VERSION 5.7 ;
  NOWIREEXTENSIONATPIN ON ;
  DIVIDERCHAR "/" ;
  BUSBITCHARS "[]" ;
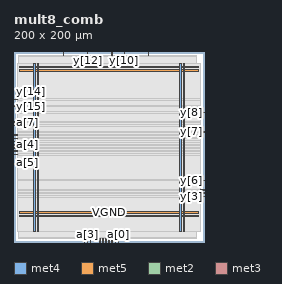
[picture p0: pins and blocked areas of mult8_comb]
MACRO mult8_comb
  CLASS BLOCK ;
  FOREIGN mult8_comb ;
  ORIGIN 0.000 0.000 ;
  SIZE 200.000 BY 200.000 ;
  PIN VGND
    DIRECTION INOUT ;
    USE GROUND ;
    PORT
      LAYER met4 ;
        RECT 24.340 10.640 25.940 187.920 ;
    END
    PORT
      LAYER met4 ;
        RECT 177.940 10.640 179.540 187.920 ;
    END
    PORT
      LAYER met5 ;
        RECT 5.280 30.030 194.360 31.630 ;
    END
    PORT
      LAYER met5 ;
        RECT 5.280 183.210 194.360 184.810 ;
    END
  END VGND
  PIN VPWR
    DIRECTION INOUT ;
    USE POWER ;
    PORT
      LAYER met4 ;
        RECT 21.040 10.640 22.640 187.920 ;
    END
    PORT
      LAYER met4 ;
        RECT 174.640 10.640 176.240 187.920 ;
    END
    PORT
      LAYER met5 ;
        RECT 5.280 26.730 194.360 28.330 ;
    END
    PORT
      LAYER met5 ;
        RECT 5.280 179.910 194.360 181.510 ;
    END
  END VPWR
  PIN a[0]
    DIRECTION INPUT ;
    USE SIGNAL ;
    ANTENNAGATEAREA 0.126000 ;
    PORT
      LAYER met2 ;
        RECT 109.570 0.000 109.850 4.000 ;
    END
  END a[0]
  PIN a[1]
    DIRECTION INPUT ;
    USE SIGNAL ;
    ANTENNAGATEAREA 0.196500 ;
    PORT
      LAYER met2 ;
        RECT 106.350 0.000 106.630 4.000 ;
    END
  END a[1]
  PIN a[2]
    DIRECTION INPUT ;
    USE SIGNAL ;
    ANTENNAGATEAREA 0.213000 ;
    PORT
      LAYER met2 ;
        RECT 90.250 0.000 90.530 4.000 ;
    END
  END a[2]
  PIN a[3]
    DIRECTION INPUT ;
    USE SIGNAL ;
    ANTENNAGATEAREA 0.213000 ;
    PORT
      LAYER met2 ;
        RECT 77.370 0.000 77.650 4.000 ;
    END
  END a[3]
  PIN a[4]
    DIRECTION INPUT ;
    USE SIGNAL ;
    ANTENNAGATEAREA 0.495000 ;
    PORT
      LAYER met3 ;
        RECT 0.000 102.040 4.000 102.640 ;
    END
  END a[4]
  PIN a[5]
    DIRECTION INPUT ;
    USE SIGNAL ;
    ANTENNAGATEAREA 0.495000 ;
    PORT
      LAYER met3 ;
        RECT 0.000 91.840 4.000 92.440 ;
    END
  END a[5]
  PIN a[6]
    DIRECTION INPUT ;
    USE SIGNAL ;
    ANTENNAGATEAREA 0.126000 ;
    PORT
      LAYER met3 ;
        RECT 0.000 112.240 4.000 112.840 ;
    END
  END a[6]
  PIN a[7]
    DIRECTION INPUT ;
    USE SIGNAL ;
    ANTENNAGATEAREA 0.196500 ;
    PORT
      LAYER met3 ;
        RECT 0.000 125.840 4.000 126.440 ;
    END
  END a[7]
  PIN b[0]
    DIRECTION INPUT ;
    USE SIGNAL ;
    ANTENNAGATEAREA 0.126000 ;
    PORT
      LAYER met2 ;
        RECT 93.470 0.000 93.750 4.000 ;
    END
  END b[0]
  PIN b[1]
    DIRECTION INPUT ;
    USE SIGNAL ;
    ANTENNAGATEAREA 0.196500 ;
    PORT
      LAYER met2 ;
        RECT 80.590 0.000 80.870 4.000 ;
    END
  END b[1]
  PIN b[2]
    DIRECTION INPUT ;
    USE SIGNAL ;
    ANTENNAGATEAREA 0.196500 ;
    PORT
      LAYER met2 ;
        RECT 74.150 0.000 74.430 4.000 ;
    END
  END b[2]
  PIN b[3]
    DIRECTION INPUT ;
    USE SIGNAL ;
    ANTENNAGATEAREA 0.196500 ;
    PORT
      LAYER met3 ;
        RECT 0.000 95.240 4.000 95.840 ;
    END
  END b[3]
  PIN b[4]
    DIRECTION INPUT ;
    USE SIGNAL ;
    ANTENNAGATEAREA 0.196500 ;
    PORT
      LAYER met3 ;
        RECT 0.000 108.840 4.000 109.440 ;
    END
  END b[4]
  PIN b[5]
    DIRECTION INPUT ;
    USE SIGNAL ;
    ANTENNAGATEAREA 0.213000 ;
    PORT
      LAYER met3 ;
        RECT 0.000 105.440 4.000 106.040 ;
    END
  END b[5]
  PIN b[6]
    DIRECTION INPUT ;
    USE SIGNAL ;
    ANTENNAGATEAREA 0.196500 ;
    PORT
      LAYER met3 ;
        RECT 0.000 98.640 4.000 99.240 ;
    END
  END b[6]
  PIN b[7]
    DIRECTION INPUT ;
    USE SIGNAL ;
    ANTENNAGATEAREA 0.213000 ;
    PORT
      LAYER met3 ;
        RECT 0.000 122.440 4.000 123.040 ;
    END
  END b[7]
  PIN y[0]
    DIRECTION OUTPUT ;
    USE SIGNAL ;
    ANTENNADIFFAREA 0.445500 ;
    PORT
      LAYER met2 ;
        RECT 96.690 0.000 96.970 4.000 ;
    END
  END y[0]
  PIN y[10]
    DIRECTION OUTPUT ;
    USE SIGNAL ;
    ANTENNADIFFAREA 1.336500 ;
    PORT
      LAYER met2 ;
        RECT 116.010 196.000 116.290 200.000 ;
    END
  END y[10]
  PIN y[11]
    DIRECTION OUTPUT ;
    USE SIGNAL ;
    ANTENNADIFFAREA 1.336500 ;
    PORT
      LAYER met2 ;
        RECT 103.130 196.000 103.410 200.000 ;
    END
  END y[11]
  PIN y[12]
    DIRECTION OUTPUT ;
    USE SIGNAL ;
    ANTENNADIFFAREA 0.891000 ;
    PORT
      LAYER met2 ;
        RECT 77.370 196.000 77.650 200.000 ;
    END
  END y[12]
  PIN y[13]
    DIRECTION OUTPUT ;
    USE SIGNAL ;
    ANTENNADIFFAREA 1.782000 ;
    PORT
      LAYER met2 ;
        RECT 51.610 196.000 51.890 200.000 ;
    END
  END y[13]
  PIN y[14]
    DIRECTION OUTPUT ;
    USE SIGNAL ;
    ANTENNADIFFAREA 1.336500 ;
    PORT
      LAYER met3 ;
        RECT 0.000 149.640 4.000 150.240 ;
    END
  END y[14]
  PIN y[15]
    DIRECTION OUTPUT ;
    USE SIGNAL ;
    ANTENNADIFFAREA 1.782000 ;
    PORT
      LAYER met3 ;
        RECT 0.000 142.840 4.000 143.440 ;
    END
  END y[15]
  PIN y[1]
    DIRECTION OUTPUT ;
    USE SIGNAL ;
    ANTENNADIFFAREA 0.445500 ;
    PORT
      LAYER met2 ;
        RECT 99.910 0.000 100.190 4.000 ;
    END
  END y[1]
  PIN y[2]
    DIRECTION OUTPUT ;
    USE SIGNAL ;
    ANTENNADIFFAREA 0.445500 ;
    PORT
      LAYER met2 ;
        RECT 103.130 0.000 103.410 4.000 ;
    END
  END y[2]
  PIN y[3]
    DIRECTION OUTPUT ;
    USE SIGNAL ;
    ANTENNADIFFAREA 0.445500 ;
    PORT
      LAYER met3 ;
        RECT 196.000 47.640 200.000 48.240 ;
    END
  END y[3]
  PIN y[4]
    DIRECTION OUTPUT ;
    USE SIGNAL ;
    ANTENNADIFFAREA 0.445500 ;
    PORT
      LAYER met3 ;
        RECT 196.000 51.040 200.000 51.640 ;
    END
  END y[4]
  PIN y[5]
    DIRECTION OUTPUT ;
    USE SIGNAL ;
    ANTENNADIFFAREA 0.445500 ;
    PORT
      LAYER met3 ;
        RECT 196.000 54.440 200.000 55.040 ;
    END
  END y[5]
  PIN y[6]
    DIRECTION OUTPUT ;
    USE SIGNAL ;
    ANTENNADIFFAREA 0.445500 ;
    PORT
      LAYER met3 ;
        RECT 196.000 64.640 200.000 65.240 ;
    END
  END y[6]
  PIN y[7]
    DIRECTION OUTPUT ;
    USE SIGNAL ;
    ANTENNADIFFAREA 0.445500 ;
    PORT
      LAYER met3 ;
        RECT 196.000 115.640 200.000 116.240 ;
    END
  END y[7]
  PIN y[8]
    DIRECTION OUTPUT ;
    USE SIGNAL ;
    ANTENNADIFFAREA 0.445500 ;
    PORT
      LAYER met3 ;
        RECT 196.000 136.040 200.000 136.640 ;
    END
  END y[8]
  PIN y[9]
    DIRECTION OUTPUT ;
    USE SIGNAL ;
    ANTENNADIFFAREA 1.336500 ;
    PORT
      LAYER met2 ;
        RECT 141.770 196.000 142.050 200.000 ;
    END
  END y[9]
  OBS
      LAYER nwell ;
        RECT 5.330 10.795 194.310 187.870 ;
      LAYER li1 ;
        RECT 5.520 10.795 194.120 187.765 ;
      LAYER met1 ;
        RECT 4.210 10.640 194.120 187.920 ;
      LAYER met2 ;
        RECT 4.230 195.720 51.330 196.000 ;
        RECT 52.170 195.720 77.090 196.000 ;
        RECT 77.930 195.720 102.850 196.000 ;
        RECT 103.690 195.720 115.730 196.000 ;
        RECT 116.570 195.720 141.490 196.000 ;
        RECT 142.330 195.720 192.190 196.000 ;
        RECT 4.230 4.280 192.190 195.720 ;
        RECT 4.230 4.000 73.870 4.280 ;
        RECT 74.710 4.000 77.090 4.280 ;
        RECT 77.930 4.000 80.310 4.280 ;
        RECT 81.150 4.000 89.970 4.280 ;
        RECT 90.810 4.000 93.190 4.280 ;
        RECT 94.030 4.000 96.410 4.280 ;
        RECT 97.250 4.000 99.630 4.280 ;
        RECT 100.470 4.000 102.850 4.280 ;
        RECT 103.690 4.000 106.070 4.280 ;
        RECT 106.910 4.000 109.290 4.280 ;
        RECT 110.130 4.000 192.190 4.280 ;
      LAYER met3 ;
        RECT 3.990 150.640 196.000 187.845 ;
        RECT 4.400 149.240 196.000 150.640 ;
        RECT 3.990 143.840 196.000 149.240 ;
        RECT 4.400 142.440 196.000 143.840 ;
        RECT 3.990 137.040 196.000 142.440 ;
        RECT 3.990 135.640 195.600 137.040 ;
        RECT 3.990 126.840 196.000 135.640 ;
        RECT 4.400 125.440 196.000 126.840 ;
        RECT 3.990 123.440 196.000 125.440 ;
        RECT 4.400 122.040 196.000 123.440 ;
        RECT 3.990 116.640 196.000 122.040 ;
        RECT 3.990 115.240 195.600 116.640 ;
        RECT 3.990 113.240 196.000 115.240 ;
        RECT 4.400 111.840 196.000 113.240 ;
        RECT 3.990 109.840 196.000 111.840 ;
        RECT 4.400 108.440 196.000 109.840 ;
        RECT 3.990 106.440 196.000 108.440 ;
        RECT 4.400 105.040 196.000 106.440 ;
        RECT 3.990 103.040 196.000 105.040 ;
        RECT 4.400 101.640 196.000 103.040 ;
        RECT 3.990 99.640 196.000 101.640 ;
        RECT 4.400 98.240 196.000 99.640 ;
        RECT 3.990 96.240 196.000 98.240 ;
        RECT 4.400 94.840 196.000 96.240 ;
        RECT 3.990 92.840 196.000 94.840 ;
        RECT 4.400 91.440 196.000 92.840 ;
        RECT 3.990 65.640 196.000 91.440 ;
        RECT 3.990 64.240 195.600 65.640 ;
        RECT 3.990 55.440 196.000 64.240 ;
        RECT 3.990 54.040 195.600 55.440 ;
        RECT 3.990 52.040 196.000 54.040 ;
        RECT 3.990 50.640 195.600 52.040 ;
        RECT 3.990 48.640 196.000 50.640 ;
        RECT 3.990 47.240 195.600 48.640 ;
        RECT 3.990 10.715 196.000 47.240 ;
  END
END mult8_comb
END LIBRARY

